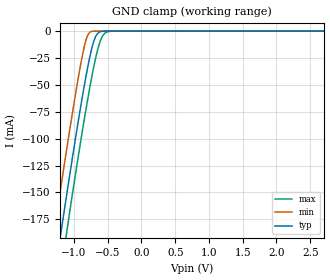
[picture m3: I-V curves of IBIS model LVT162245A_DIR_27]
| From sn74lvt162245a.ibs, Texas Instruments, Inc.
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[Model]   LVT162245A_DIR_27
Model_type  Input
Vinl=0.8
Vinh=2.0
| variable   typ   min   max
C_comp   4.26pF   3.18pF   5.38pF
[Temperature Range]   40   -40   100
| Ambient temperature   25   -40   85
[Voltage range]   2.7   2.7   2.7
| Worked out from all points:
|   GND clamp passes 1 mA (typ) near -0.62 V on its own axis
[GND Clamp]
| LVT162245A_DIR_27
|   Voltage   I(typ)   I(min)   I(max)
-5.5V     -2.536A    -2.484A    -2.58A
-1.295V   -230.8mA   -187.3mA   -271.4mA
-1.185V   -184.1mA   -141.5mA   -221.1mA
-1.11V    -153.1mA   -110.9mA   -188.2mA
-1.09V    -144.9mA   -102.8mA   -179.7mA
-920mV    -77.66mA   -37.72mA   -110.3mA
-815mV    -39.77mA   -7.053mA   -70.28mA
-770mV    -25.5mA    -1.491mA   -54.14mA
-685mV    -5.986mA   -29.13uA   -26.8mA
-615mV    -749.8uA   -999nA     -10.14mA
-540mV    -53.88uA   -26.89nA   -1.88mA
2.7V      8.656pA    8.216pA    1.554nA
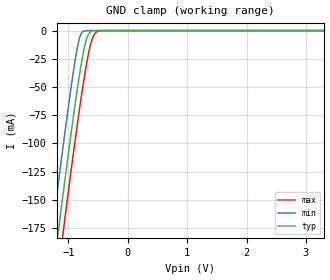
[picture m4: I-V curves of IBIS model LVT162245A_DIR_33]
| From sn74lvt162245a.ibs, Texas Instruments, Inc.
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[Model]   LVT162245A_DIR_33
Model_type  Input
Vinl=0.8
Vinh=2.0
| variable   typ   min   max
C_comp   4.22pF   3.07pF   5.33pF
[Temperature Range]   40   -40   100
| Ambient temperature   25   -40   85
[Voltage range]   3.3   3   3.6
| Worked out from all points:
|   GND clamp passes 1 mA (typ) near -0.62 V on its own axis
[GND Clamp]
| LVT162245A_DIR_33
|   Voltage   I(typ)   I(min)   I(max)
-5.5V     -2.536A    -2.484A    -2.58A
-1.275V   -222.1mA   -178.9mA   -262.1mA
-1.17V    -177.8mA   -135.3mA   -214.4mA
-1.1V     -149mA     -106.9mA   -184mA
-1.08V    -140.9mA   -98.84mA   -175.5mA
-920mV    -77.66mA   -37.72mA   -110.3mA
-810mV    -38.1mA    -6.134mA   -68.45mA
-735mV    -15.92mA   -314.5uA   -42.26mA
-680mV    -5.295mA   -22.91uA   -25.39mA
-600mV    -449uA     -484.7nA   -7.654mA
-530mV    -37.67uA   -16.61nA   -1.435mA
3.3V      10.58pA    10.16pA    2.805nA
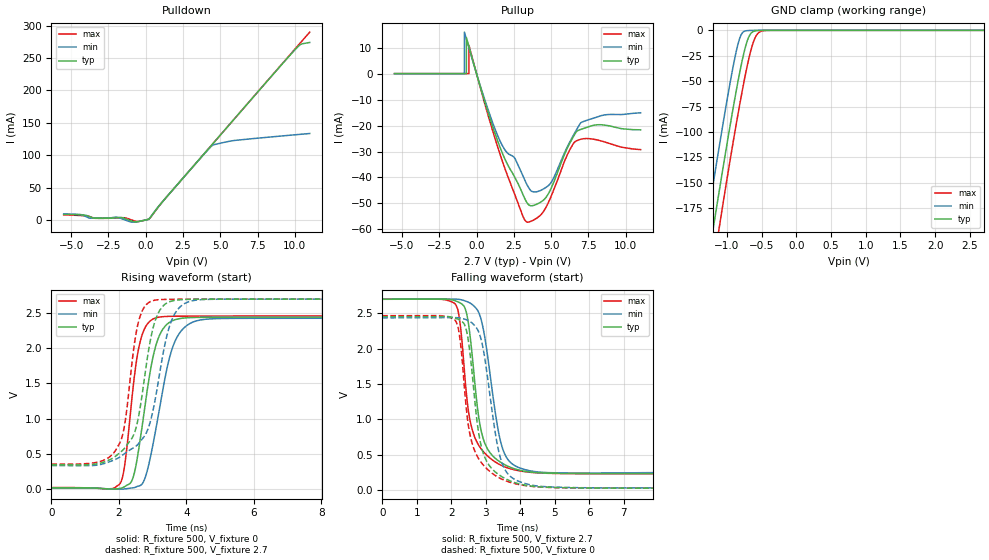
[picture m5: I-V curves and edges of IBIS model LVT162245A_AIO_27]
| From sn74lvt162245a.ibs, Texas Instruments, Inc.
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[Model]   LVT162245A_AIO_27
Model_type  3-state
Enable   Active-Low
Vref =   0
Rref =   500
Cref =   50p
Vmeas =   1.5
| variable   typ   min   max
C_comp   10pF   NA   NA
| C_pullup   3.99pF   2.71pF   5.44pF
| C_pulldown   4.93pF   3.51pF   6.08pF
| C_tri-state   5.61pF   4.29pF   6.86pF
[Temperature Range]   40   -40   100
| Ambient temperature   25   -40   85
[Voltage range]   2.7   2.7   2.7
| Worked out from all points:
|   slope of the pulldown table from 0 to 0.405 V, typ, clamps not added: 59.7 ohm
|   slope of the pullup table from 0 to 0.405 V, typ, clamps not added: 50.7 ohm
|   GND clamp passes 1 mA (typ) near -0.62 V on its own axis
|   rising waveform, R_fixture 500, V_fixture 0: 20-80 % time 484ps typ, 594ps min, 358ps max; typ from 0.014 V to 2.44 V
|   falling waveform, R_fixture 500, V_fixture 2.7: 20-80 % time 346ps typ, 424ps min, 356ps max; typ from 2.7 V to 0.336 V
|   rising waveform, R_fixture 500, V_fixture 2.7: 20-80 % time 510ps typ, 627ps min, 381ps max; typ from 0.341 V to 2.7 V
|   falling waveform, R_fixture 500, V_fixture 0: 20-80 % time 403ps typ, 458ps min, 432ps max; typ from 2.45 V to 0.016 V
[GND Clamp]
| LVT162245A_AIO_27
|   Voltage   I(typ)   I(min)   I(max)
-5.5V     -2.604A    -2.543A    -2.654A
-1.31V    -244mA     -198.9mA   -286.1mA
-1.27V    -226.3mA   -181.7mA   -267mA
-1.19V    -191.6mA   -147.5mA   -229.6mA
-1.115V   -159.8mA   -116mA     -195.9mA
-1.07V    -140.9mA   -97.42mA   -176.3mA
-920mV    -80.12mA   -38.82mA   -113.7mA
-815mV    -41.17mA   -7.619mA   -72.65mA
-685mV    -6.472mA   -171.4uA   -27.98mA
-605mV    -728.7uA   -14.11uA   -9.051mA
-535mV    -95.19uA   -532.8nA   -1.916mA
2.7V      19.79pA    18.32pA    3.26nA
[Pulldown]
| LVT162245A_AIO_27
|   Voltage   I(typ)   I(min)   I(max)
-5.5V     8.64mA     9.26mA     7.772mA
-4.325V   7.766mA    8.153mA    6.734mA
-3.74V    4.898mA    2.719mA    5.056mA
-1.955V   3.391mA    4.259mA    2.949mA
-900mV    -2.124mA   -3.464mA   -464.5uA
-485mV    -2.443mA   -2.427mA   -2.414mA
230mV     1.616mA    1.769mA    1.952mA
4.505V    117.8mA    115.5mA    117.7mA
5.955V    156.3mA    122.7mA    156.3mA
10.1V     264.7mA    131.6mA    266.1mA
10.43V    271.3mA    132.3mA    274.8mA
11V       273.9mA    133.4mA    289.9mA
[Pullup]
| LVT162245A_AIO_27
|   Voltage   I(typ)   I(min)   I(max)
-5.5V     59.99uA    40.77uA    89.25uA
-820mV    52.81uA    31.04uA    79.22uA
-815mV    52.66uA    16.1mA     79.19uA
-685mV    35.69uA    13.45mA    75.8uA
-680mV    13.98mA    13.34mA    75.51uA
-515mV    10.55mA    10.02mA    47.19uA
-510mV    10.44mA    9.924mA    10.99mA
1.43V     -26.14mA   -24.06mA   -28.48mA
3.385V    -49.78mA   -42.83mA   -57.22mA
4.9V      -45.35mA   -42.68mA   -48.61mA
6.63V     -22.89mA   -22.34mA   -26.09mA
11V       -21.62mA   -15.05mA   -29.26mA
[Ramp]
| LVT162245A_AIO_27
| variable   typ   min   max
dV/dt_r   1.47/4.88E-10   1.46/5.98E-10   1.48/3.61E-10
dV/dt_f   1.48/3.93E-10   1.48/4.60E-10   1.48/4.16E-10
R_load = 500
[Rising Waveform]
| LVT162245A_AIO_27
R_fixture =   500
C_fixture =   0
L_fixture =   0
V_fixture =   0
V_fixture_min = 0
V_fixture_max = 0
|   Time   V(typ)   V(min)   V(max)
0s        13.73mV    9.71mV     17.71mV
2.015ns   4.127mV    -5.293mV   64.9mV
2.165ns   29.29mV    -2.099mV   315.9mV
2.355ns   90.92mV    10.37mV    1.138V
2.69ns    896.1mV    69.18mV    2.193V
2.99ns    1.829V     582.8mV    2.41V
3.265ns   2.243V     1.309V     2.448V
3.78ns    2.42V      2.204V     2.456V
4.765ns   2.441V     2.419V     2.458V
50ns      2.444V     2.429V     2.46V
[Falling Waveform]
| LVT162245A_AIO_27
R_fixture =   500
C_fixture =   0
L_fixture =   0
V_fixture =   2.7
V_fixture_min = 2.7
V_fixture_max = 2.7
|   Time   V(typ)   V(min)   V(max)
0s        2.7V       2.7V       2.7V
2.115ns   2.678V     2.702V     2.634V
2.26ns    2.647V     2.695V     2.339V
2.445ns   2.495V     2.669V     1.329V
2.705ns   1.403V     2.58V      716.7mV
2.96ns    675.5mV    2.192V     526.2mV
3.305ns   436.2mV    1V         386.8mV
3.49ns    374.1mV    581.5mV    339.3mV
4.285ns   254.2mV    270.6mV    250.5mV
50ns      336.1mV    342mV      325.1mV
[Rising Waveform]
| LVT162245A_AIO_27
R_fixture =   500
C_fixture =   0
L_fixture =   0
V_fixture =   2.7
V_fixture_min = 2.7
V_fixture_max = 2.7
|   Time   V(typ)   V(min)   V(max)
0s        341.3mV    330.8mV    350.2mV
1.835ns   441mV      405.5mV    503.3mV
2.13ns    556.5mV    486.4mV    809.4mV
2.355ns   697.9mV    561.2mV    1.654V
2.65ns    1.218V     684.6mV    2.485V
2.935ns   2.12V      963.6mV    2.664V
3.15ns    2.484V     1.476V     2.69V
3.63ns    2.679V     2.468V     2.697V
4.46ns    2.698V     2.692V     2.699V
50ns      2.7V       2.7V       2.7V
[Falling Waveform]
| LVT162245A_AIO_27
R_fixture =   500
C_fixture =   0
L_fixture =   0
V_fixture =   0
V_fixture_min = 0
V_fixture_max = 0
|   Time   V(typ)   V(min)   V(max)
0s        2.454V     2.438V     2.467V
2.11ns    2.434V     2.44V      2.405V
2.255ns   2.402V     2.434V     2.124V
2.435ns   2.267V     2.41V      1.155V
2.68ns    1.267V     2.326V     553.1mV
2.94ns    500.3mV    1.954V     346.7mV
3.28ns    253.2mV    790.2mV    203.4mV
3.475ns   185.2mV    375.7mV    151mV
4.35ns    53.45mV    66.47mV    50.1mV
50ns      15.83mV    11.68mV    19.93mV
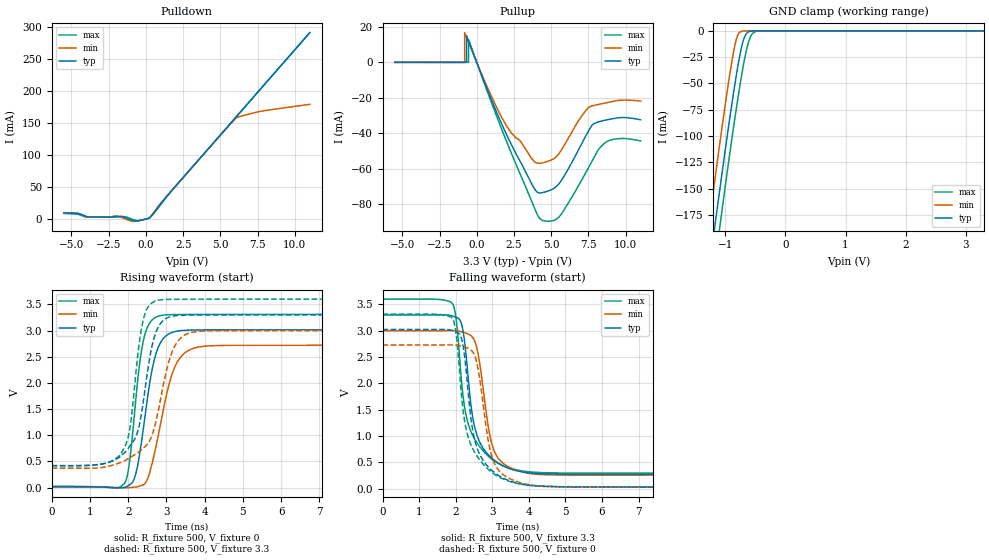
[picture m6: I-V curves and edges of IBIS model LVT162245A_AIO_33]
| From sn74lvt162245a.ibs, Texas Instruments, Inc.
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[Model]   LVT162245A_AIO_33
Model_type  3-state
Enable   Active-Low
Vref =   0
Rref =   500
Cref =   50p
Vmeas =   1.5
| variable   typ   min   max
C_comp   10pF   NA   NA
| C_pullup   3.61pF   2.50pF   4.87pF
| C_pulldown   4.79pF   3.18pF   6.10pF
| C_tri-state   5.52pF   4.15pF   6.75pF
[Temperature Range]   40   -40   100
| Ambient temperature   25   -40   85
[Voltage range]   3.3   3   3.6
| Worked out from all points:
|   slope of the pulldown table from 0 to 0.495 V, typ, clamps not added: 61.9 ohm
|   slope of the pullup table from 0 to 0.495 V, typ, clamps not added: 46.1 ohm
|   GND clamp passes 1 mA (typ) near -0.62 V on its own axis
|   rising waveform, R_fixture 500, V_fixture 0: 20-80 % time 380ps typ, 496ps min, 290ps max; typ from 0.018 V to 3.02 V
|   falling waveform, R_fixture 500, V_fixture 3.3: 20-80 % time 347ps typ, 339ps min, 388ps max; typ from 3.3 V to 0.393 V
|   rising waveform, R_fixture 500, V_fixture 3.3: 20-80 % time 415ps typ, 529ps min, 305ps max; typ from 0.421 V to 3.3 V
|   falling waveform, R_fixture 500, V_fixture 0: 20-80 % time 419ps typ, 381ps min, 470ps max; typ from 3.02 V to 0.02 V
[GND Clamp]
| LVT162245A_AIO_33
|   Voltage   I(typ)   I(min)   I(max)
-5.5V     -2.609A    -2.545A    -2.66A
-1.305V   -242.3mA   -197mA     -284.2mA
-1.265V   -224.5mA   -179.8mA   -265mA
-1.185V   -189.8mA   -145.7mA   -227.7mA
-1.105V   -155.9mA   -112.1mA   -191.9mA
-1.06V    -137.1mA   -93.49mA   -172.3mA
-920mV    -80.32mA   -38.88mA   -113.9mA
-810mV    -39.55mA   -6.7mA     -70.9mA
-680mV    -5.782mA   -155.7uA   -26.58mA
-605mV    -735uA     -14.18uA   -9.076mA
-530mV    -82.28uA   -417.7nA   -1.694mA
3.3V      24.36pA    24.93pA    5.428nA
[Pulldown]
| LVT162245A_AIO_33
|   Voltage   I(typ)   I(min)   I(max)
-5.5V     9.531mA    9.918mA    8.757mA
-4.54V    8.474mA    8.859mA    7.118mA
-3.92V    3.524mA    3.011mA    2.875mA
-1.965V   3.887mA    4.696mA    3.338mA
-1.42V    2.669mA    459.6uA    3.618mA
-895mV    -2.165mA   -3.544mA   -496.8uA
-480mV    -2.527mA   -2.475mA   -2.532mA
245mV     1.861mA    1.55mA     2.449mA
1.255V    31.47mA    31.79mA    30.61mA
6.095V    160.5mA    158.3mA    160.5mA
7.79V     205.7mA    168.7mA    205.8mA
11V       291.2mA    179.2mA    291.3mA
[Pullup]
| LVT162245A_AIO_33
|   Voltage   I(typ)   I(min)   I(max)
-5.5V     77.62uA    47.9uA     122uA
-815mV    68.57uA    33.52uA    111.3uA
-810mV    68.29uA    16.88mA    111.2uA
-685mV    43.37uA    14.22mA    96.36uA
-680mV    15.09mA    14.12mA    95.13uA
-550mV    12.19mA    11.37mA    71.67uA
-545mV    12.08mA    11.27mA    12.78mA
2.005V    -40.78mA   -35.78mA   -44.63mA
4.465V    -73.29mA   -56.56mA   -89.25mA
5.625V    -67.17mA   -50.1mA    -86.1mA
7.81V     -34.82mA   -24.36mA   -54.57mA
11V       -32.33mA   -21.72mA   -44.29mA
[Ramp]
| LVT162245A_AIO_33
| variable   typ   min   max
dV/dt_r   1.81/3.88E-10   1.63/5.04E-10   1.99/2.96E-10
dV/dt_f   1.82/4.05E-10   1.65/3.76E-10   1.99/4.54E-10
R_load = 500
[Rising Waveform]
| LVT162245A_AIO_33
R_fixture =   500
C_fixture =   0
L_fixture =   0
V_fixture =   0
V_fixture_min = 0
V_fixture_max = 0
|   Time   V(typ)   V(min)   V(max)
0s        17.92mV    11.67mV    23.24mV
1.91ns    5.931mV    -4.532mV   89.73mV
2.03ns    52.63mV    -163.4uV   464.2mV
2.18ns    214.9mV    10.22mV    1.536V
2.415ns   1.226V     63.5mV     2.863V
2.67ns    2.402V     596.9mV    3.229V
2.96ns    2.88V      1.631V     3.298V
3.385ns   2.999V     2.505V     3.306V
4.24ns    3.013V     2.711V     3.308V
50ns      3.016V     2.72V      3.309V
[Falling Waveform]
| LVT162245A_AIO_33
R_fixture =   500
C_fixture =   0
L_fixture =   0
V_fixture =   3.3
V_fixture_min = 3
V_fixture_max = 3.6
|   Time   V(typ)   V(min)   V(max)
0s        3.3V       3V         3.6V
1.92ns    3.279V     3.002V     3.505V
2.025ns   3.252V     2.997V     3.146V
2.185ns   3.053V     2.976V     1.855V
2.435ns   1.491V     2.897V     1.053V
2.6ns     978.2mV    2.599V     851mV
2.895ns   639.4mV    1.155V     612.6mV
3.065ns   533.6mV    696mV      520mV
4.025ns   296.8mV    286.7mV    316.9mV
50ns      392.7mV    365.7mV    406.5mV
[Rising Waveform]
| LVT162245A_AIO_33
R_fixture =   500
C_fixture =   0
L_fixture =   0
V_fixture =   3.3
V_fixture_min = 3
V_fixture_max = 3.6
|   Time   V(typ)   V(min)   V(max)
0s        421mV      371.4mV    413.7mV
1.81ns    604.4mV    480.8mV    645.2mV
2.035ns   785.5mV    568mV      1.094V
2.245ns   1.061V     662.8mV    2.494V
2.405ns   1.691V     759mV      3.235V
2.645ns   2.772V     1.047V     3.539V
2.905ns   3.185V     1.907V     3.59V
3.295ns   3.287V     2.793V     3.596V
4.065ns   3.298V     2.994V     3.599V
50ns      3.3V       3V         3.6V
[Falling Waveform]
| LVT162245A_AIO_33
R_fixture =   500
C_fixture =   0
L_fixture =   0
V_fixture =   0
V_fixture_min = 0
V_fixture_max = 0
|   Time   V(typ)   V(min)   V(max)
0s        3.023V     2.728V     3.315V
1.92ns    3.003V     2.73V      3.22V
2.025ns   2.975V     2.725V     2.86V
2.185ns   2.775V     2.704V     1.587V
2.435ns   1.234V     2.622V     802.4mV
2.595ns   750.7mV    2.332V     605.9mV
2.88ns    418.5mV    945.8mV    371.8mV
3.06ns    304.1mV    478.4mV    272.1mV
4.065ns   58.11mV    67.07mV    57.14mV
50ns      20.34mV    13.53mV    25.87mV
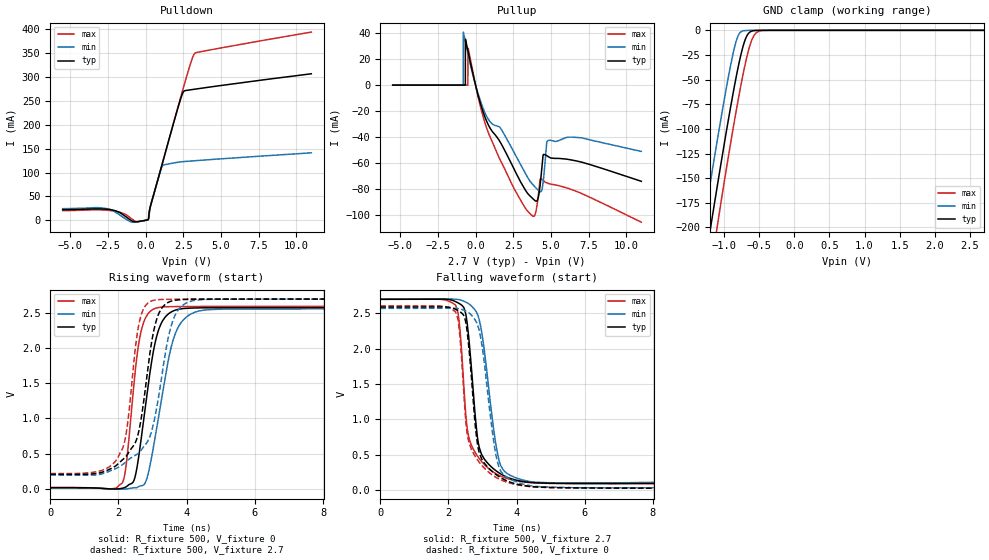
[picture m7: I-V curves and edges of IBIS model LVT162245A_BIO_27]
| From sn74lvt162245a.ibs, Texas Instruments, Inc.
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[Model]   LVT162245A_BIO_27
Model_type  3-state
Enable   Active-Low
Vref =   0
Rref =   500
Cref =   50p
Vmeas =   1.5
| variable   typ   min   max
C_comp   10pF   NA   NA
| C_pullup   5.97pF   3.34pF   8.80pF
| C_pulldown   5.72pF   4.51pF   7.32pF
| C_tri-state   5.72pF   4.46pF   7.19pF
[Temperature Range]   40   -40   100
| Ambient temperature   25   -40   85
[Voltage range]   2.7   2.7   2.7
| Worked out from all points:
|   slope of the pulldown table from 0 to 0.405 V, typ, clamps not added: 10.4 ohm
|   slope of the pullup table from 0 to 0.405 V, typ, clamps not added: 23.4 ohm
|   GND clamp passes 1 mA (typ) near -0.62 V on its own axis
|   rising waveform, R_fixture 500, V_fixture 0: 20-80 % time 455ps typ, 566ps min, 329ps max; typ from 0.014 V to 2.58 V
|   falling waveform, R_fixture 500, V_fixture 2.7: 20-80 % time 279ps typ, 387ps min, 283ps max; typ from 2.7 V to 0.201 V
|   rising waveform, R_fixture 500, V_fixture 2.7: 20-80 % time 482ps typ, 605ps min, 352ps max; typ from 0.206 V to 2.7 V
|   falling waveform, R_fixture 500, V_fixture 0: 20-80 % time 316ps typ, 403ps min, 364ps max; typ from 2.59 V to 0.017 V
[GND Clamp]
| LVT162245A_BIO_27
|   Voltage   I(typ)   I(min)   I(max)
-5.5V     -2.784A    -2.724A    -2.838A
-1.3V     -248mA     -198.9mA   -302.8mA
-1.195V   -199.9mA   -152.5mA   -245.4mA
-1.125V   -168.9mA   -122.2mA   -210.6mA
-1.085V   -151.4mA   -105.2mA   -191.7mA
-910mV    -77.83mA   -35.54mA   -114.5mA
-820mV    -43.55mA   -8.707mA   -77.59mA
-775mV    -28.4mA    -2.295mA   -60.14mA
-690mV    -7.332mA   -205.3uA   -30.51mA
-615mV    -995.9uA   -21.76uA   -11.18mA
-535mV    -97.15uA   -533.2nA   -1.981mA
2.7V      19.79pA    18.32pA    3.26nA
[Pulldown]
| LVT162245A_BIO_27
|   Voltage   I(typ)   I(min)   I(max)
-5.5V     22.18mA    24.3mA     20.11mA
-2.755V   23.49mA    25.34mA    21.47mA
-1.85V    18.18mA    13.98mA    17.83mA
-945mV    -615.9uA   -3.66mA    3.564mA
-565mV    -3.195mA   -3.269mA   -2.871mA
150mV     918uA      796.5uA    1.301mA
210mV     6.147mA    10.83mA    4.004mA
355mV     33.26mA    33.47mA    33.11mA
1.135V    121.6mA    114.5mA    121.5mA
2.465V    266.3mA    122.9mA    272.9mA
3.255V    274.7mA    124.8mA    349.6mA
11V       307.1mA    141.3mA    394.5mA
[Pullup]
| LVT162245A_BIO_27
|   Voltage   I(typ)   I(min)   I(max)
-5.5V     59.99uA    40.77uA    89.26uA
-815mV    52.71uA    31.42uA    79.2uA
-810mV    52.55uA    40.95mA    79.18uA
-685mV    35.89uA    33.99mA    75.93uA
-675mV    34.8mA     33.44mA    75.34uA
-515mV    26.83mA    24.68mA    44.39uA
-490mV    25.45mA    23.34mA    28.39mA
820mV     -29.98mA   -25.82mA   -35.79mA
3.615V    -85.46mA   -74.11mA   -99.12mA
4.525V    -53.43mA   -70.41mA   -73.84mA
4.87V     -55.44mA   -42.53mA   -75.99mA
11V       -74.14mA   -51.1mA    -105.7mA
[Ramp]
| LVT162245A_BIO_27
| variable   typ   min   max
dV/dt_r   1.55/4.64E-10   1.54/5.74E-10   1.56/3.35E-10
dV/dt_f   1.57/3.21E-10   1.56/4.13E-10   1.57/3.45E-10
R_load = 500
[Rising Waveform]
| LVT162245A_BIO_27
R_fixture =   500
C_fixture =   0
L_fixture =   0
V_fixture =   0
V_fixture_min = 0
V_fixture_max = 0
|   Time   V(typ)   V(min)   V(max)
0s        14.32mV    10.13mV    18.49mV
2.1ns     5.562mV    -5.967mV   75.86mV
2.225ns   27.29mV    -3.229mV   337.7mV
2.425ns   91.71mV    12.17mV    1.341V
2.725ns   929.5mV    50.25mV    2.348V
3.02ns    1.946V     577.9mV    2.555V
3.255ns   2.355V     1.25V      2.585V
3.76ns    2.554V     2.306V     2.593V
4.705ns   2.576V     2.551V     2.595V
50ns      2.579V     2.561V     2.596V
[Falling Waveform]
| LVT162245A_BIO_27
R_fixture =   500
C_fixture =   0
L_fixture =   0
V_fixture =   2.7
V_fixture_min = 2.7
V_fixture_max = 2.7
|   Time   V(typ)   V(min)   V(max)
0s        2.7V       2.7V       2.7V
2.21ns    2.667V     2.701V     2.617V
2.335ns   2.635V     2.692V     2.289V
2.52ns    2.465V     2.657V     1.015V
2.77ns    1.151V     2.556V     544.6mV
2.965ns   516.5mV    2.27V      410.1mV
3.34ns    294.6mV    824.8mV    248.2mV
3.505ns   237.6mV    390.9mV    203.6mV
4.29ns    113.7mV    129.9mV    110.8mV
50ns      200.8mV    206.9mV    189.3mV
[Rising Waveform]
| LVT162245A_BIO_27
R_fixture =   500
C_fixture =   0
L_fixture =   0
V_fixture =   2.7
V_fixture_min = 2.7
V_fixture_max = 2.7
|   Time   V(typ)   V(min)   V(max)
0s        206mV      194.7mV    215.8mV
1.97ns    345.5mV    298.5mV    431.8mV
2.225ns   460.6mV    386.3mV    784.5mV
2.635ns   913.7mV    530.4mV    2.418V
2.925ns   1.94V      749.1mV    2.663V
3.12ns    2.411V     1.151V     2.69V
3.42ns    2.642V     2.054V     2.696V
3.63ns    2.68V      2.437V     2.697V
4.41ns    2.698V     2.691V     2.699V
50ns      2.7V       2.7V       2.7V
[Falling Waveform]
| LVT162245A_BIO_27
R_fixture =   500
C_fixture =   0
L_fixture =   0
V_fixture =   0
V_fixture_min = 0
V_fixture_max = 0
|   Time   V(typ)   V(min)   V(max)
0s        2.59V      2.571V     2.605V
2.21ns    2.558V     2.573V     2.521V
2.33ns    2.526V     2.565V     2.215V
2.505ns   2.386V     2.535V     1.007V
2.705ns   1.417V     2.46V      549.1mV
2.81ns    817.1mV    2.389V     459.2mV
2.91ns    522.9mV    2.248V     390.6mV
3.475ns   193.3mV    341.8mV    158.8mV
4.345ns   54.3mV     66.98mV    51.56mV
50ns      16.52mV    12.18mV    20.81mV
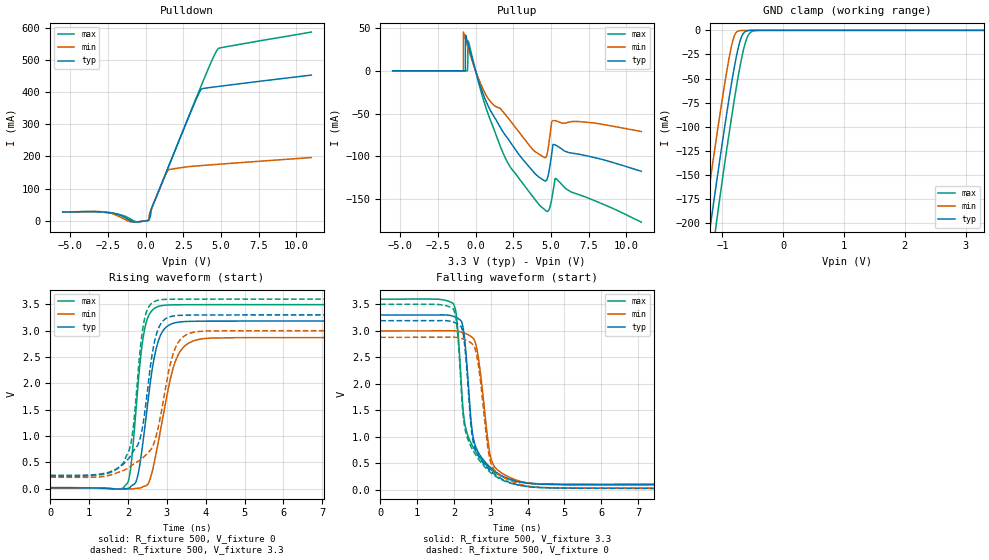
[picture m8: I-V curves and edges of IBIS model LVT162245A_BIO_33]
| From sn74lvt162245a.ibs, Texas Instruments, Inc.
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[Model]   LVT162245A_BIO_33
Model_type  3-state
Enable   Active-Low
Vref =   0
Rref =   500
Cref =   50p
Vmeas =   1.5
| variable   typ   min   max
C_comp   10pF   NA   NA
| C_pullup   6.13pF   3.12pF   9.42pF
| C_pulldown   5.61pF   4.21pF   6.99pF
| C_tri-state   5.64pF   4.27pF   6.89pF
[Temperature Range]   40   -40   100
| Ambient temperature   25   -40   85
[Voltage range]   3.3   3   3.6
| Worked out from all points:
|   slope of the pulldown table from 0 to 0.495 V, typ, clamps not added: 9.89 ohm
|   slope of the pullup table from 0 to 0.495 V, typ, clamps not added: 18.5 ohm
|   GND clamp passes 1 mA (typ) near -0.61 V on its own axis
|   rising waveform, R_fixture 500, V_fixture 0: 20-80 % time 350ps typ, 466ps min, 260ps max; typ from 0.019 V to 3.18 V
|   falling waveform, R_fixture 500, V_fixture 3.3: 20-80 % time 265ps typ, 282ps min, 337ps max; typ from 3.3 V to 0.226 V
|   rising waveform, R_fixture 500, V_fixture 3.3: 20-80 % time 384ps typ, 504ps min, 274ps max; typ from 0.258 V to 3.3 V
|   falling waveform, R_fixture 500, V_fixture 0: 20-80 % time 337ps typ, 301ps min, 420ps max; typ from 3.19 V to 0.021 V
[GND Clamp]
| LVT162245A_BIO_33
|   Voltage   I(typ)   I(min)   I(max)
-5.5V     -2.798A    -2.732A    -2.86A
-1.325V   -261.5mA   -211mA     -319.7mA
-1.295V   -247.2mA   -197.5mA   -302.1mA
-1.19V    -198.9mA   -151mA     -244.6mA
-1.1V     -159mA     -112mA     -200.2mA
-915mV    -80.34mA   -37.45mA   -117.4mA
-815mV    -42.02mA   -7.721mA   -76.14mA
-740mV    -18.27mA   -742.5uA   -47.61mA
-685mV    -6.588mA   -187.2uA   -29.15mA
-610mV    -870.8uA   -17.83uA   -10.3mA
-530mV    -83.9uA    -418nA     -1.754mA
3.3V      24.36pA    24.92pA    5.428nA
[Pulldown]
| LVT162245A_BIO_33
|   Voltage   I(typ)   I(min)   I(max)
-5.5V     27.16mA    27.02mA    27.11mA
-2.795V   27.46mA    27.75mA    26.61mA
-1.845V   20.53mA    15.25mA    20.67mA
-935mV    -496.1uA   -3.752mA   3.929mA
155mV     1.037mA    846.5uA    1.7mA
210mV     2.627mA    2.685mA    4.677mA
265mV     6.963mA    22.01mA    9.992mA
365mV     34.44mA    35.15mA    29.35mA
1.51V     166.8mA    157.9mA    166.9mA
3.635V    404.5mA    171.4mA    413.2mA
4.79V     417.2mA    175.6mA    533.3mA
11V       452.7mA    196.6mA    586.3mA
[Pullup]
| LVT162245A_BIO_33
|   Voltage   I(typ)   I(min)   I(max)
-5.5V     77.62uA    47.9uA     122uA
-815mV    68.68uA    33.7uA     111.4uA
-805mV    68.11uA    45.46mA    111.2uA
-680mV    47.26uA    37.86mA    95.81uA
-670mV    40.92mA    37.26mA    93.32uA
-545mV    34.34mA    29.73mA    76.83uA
-480mV    30.13mA    25.89mA    34.82mA
1.83V     -71.83mA   -48.11mA   -96.51mA
4.25V     -125mA     -98.1mA    -157.5mA
4.745V    -127.1mA   -97.54mA   -164.7mA
5.175V    -86.15mA   -58.35mA   -137.8mA
11V       -117.7mA   -71.13mA   -177.4mA
[Ramp]
| LVT162245A_BIO_33
| variable   typ   min   max
dV/dt_r   1.91/3.56E-10   1.73/4.72E-10   2.10/2.65E-10
dV/dt_f   1.92/3.26E-10   1.74/3.03E-10   2.10/4.09E-10
R_load = 500
[Rising Waveform]
| LVT162245A_BIO_33
R_fixture =   500
C_fixture =   0
L_fixture =   0
V_fixture =   0
V_fixture_min = 0
V_fixture_max = 0
|   Time   V(typ)   V(min)   V(max)
0s        18.69mV    12.17mV    24.28mV
1.99ns    7.729mV    -5.148mV   110.8mV
2.085ns   52.7mV     -1.421mV   487.9mV
2.23ns    187mV      10.81mV    1.713V
2.43ns    1.145V     50.99mV    3.031V
2.68ns    2.503V     511.4mV    3.422V
2.93ns    3.026V     1.479V     3.482V
3.335ns   3.165V     2.596V     3.492V
4.17ns    3.181V     2.861V     3.494V
50ns      3.184V     2.87V      3.495V
[Falling Waveform]
| LVT162245A_BIO_33
R_fixture =   500
C_fixture =   0
L_fixture =   0
V_fixture =   3.3
V_fixture_min = 3
V_fixture_max = 3.6
|   Time   V(typ)   V(min)   V(max)
0s        3.3V       3V         3.6V
1.98ns    3.277V     3.002V     3.518V
2.095ns   3.243V     2.994V     3.105V
2.255ns   3.045V     2.966V     1.466V
2.52ns    1.004V     2.863V     811.9mV
2.66ns    713mV      2.516V     655.6mV
2.925ns   468.3mV    931.5mV    436.3mV
3.03ns    399.6mV    544.4mV    372.3mV
4.04ns    123.5mV    127.3mV    129.1mV
50ns      226.2mV    214.6mV    225.5mV
[Rising Waveform]
| LVT162245A_BIO_33
R_fixture =   500
C_fixture =   0
L_fixture =   0
V_fixture =   3.3
V_fixture_min = 3
V_fixture_max = 3.6
|   Time   V(typ)   V(min)   V(max)
0s        257.9mV    220.3mV    233.4mV
1.88ns    469mV      348.7mV    494.6mV
2.105ns   675.3mV    447.2mV    992.9mV
2.3ns     926mV      540.5mV    2.532V
2.43ns    1.439V     619.2mV    3.234V
2.655ns   2.688V     841.1mV    3.542V
2.865ns   3.153V     1.485V     3.589V
3.27ns    3.288V     2.748V     3.597V
3.98ns    3.299V     2.992V     3.599V
50ns      3.3V       3V         3.6V
[Falling Waveform]
| LVT162245A_BIO_33
R_fixture =   500
C_fixture =   0
L_fixture =   0
V_fixture =   0
V_fixture_min = 0
V_fixture_max = 0
|   Time   V(typ)   V(min)   V(max)
0s        3.192V     2.879V     3.501V
1.98ns    3.169V     2.881V     3.418V
2.095ns   3.135V     2.873V     3.002V
2.255ns   2.934V     2.846V     1.382V
2.505ns   979.4mV    2.747V     763.9mV
2.65ns    660.4mV    2.422V     600.4mV
2.905ns   419.9mV    884.9mV    384.8mV
3.025ns   340.5mV    466.9mV    310.6mV
4.065ns   58.51mV    65.99mV    58.27mV
50ns      21.23mV    14.1mV     27.04mV
